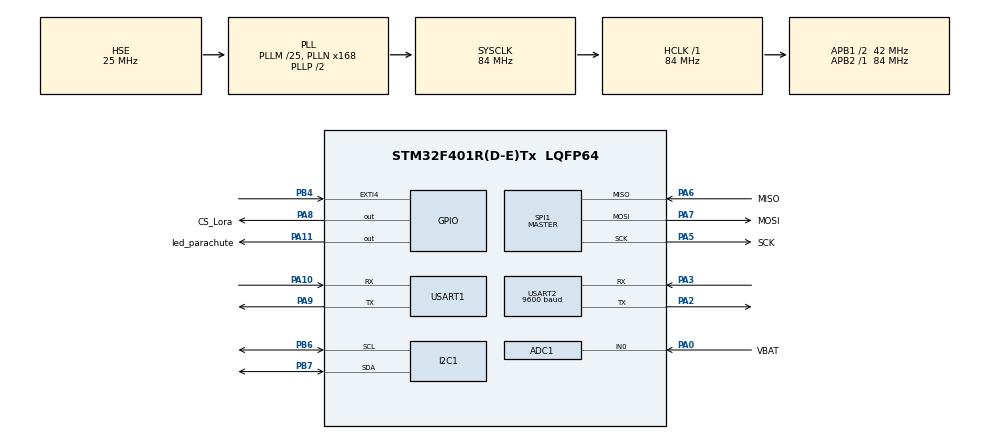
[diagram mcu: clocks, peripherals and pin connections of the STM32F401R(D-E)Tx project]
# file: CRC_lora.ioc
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ADC1.Channel-0\#ChannelRegularConversion=ADC_CHANNEL_0
ADC1.ClockPrescaler=ADC_CLOCK_SYNC_PCLK_DIV8
ADC1.ContinuousConvMode=ENABLE
ADC1.NbrOfConversionFlag=1
ADC1.Rank-0\#ChannelRegularConversion=1
ADC1.SamplingTime-0\#ChannelRegularConversion=ADC_SAMPLETIME_3CYCLES
ADC1.master=1
Dma.I2C1_RX.1.Direction=DMA_PERIPH_TO_MEMORY
Dma.I2C1_RX.1.FIFOMode=DMA_FIFOMODE_DISABLE
Dma.I2C1_RX.1.Instance=DMA1_Stream0
Dma.I2C1_RX.1.MemDataAlignment=DMA_MDATAALIGN_BYTE
Dma.I2C1_RX.1.MemInc=DMA_MINC_ENABLE
Dma.I2C1_RX.1.Mode=DMA_NORMAL
Dma.I2C1_RX.1.PeriphDataAlignment=DMA_PDATAALIGN_BYTE
Dma.I2C1_RX.1.PeriphInc=DMA_PINC_DISABLE
Dma.I2C1_RX.1.Priority=DMA_PRIORITY_LOW
Dma.Request0=USART2_RX
Dma.Request1=I2C1_RX
Dma.USART2_RX.0.Direction=DMA_PERIPH_TO_MEMORY
Dma.USART2_RX.0.FIFOMode=DMA_FIFOMODE_DISABLE
Dma.USART2_RX.0.Instance=DMA1_Stream5
Dma.USART2_RX.0.MemDataAlignment=DMA_MDATAALIGN_BYTE
Dma.USART2_RX.0.MemInc=DMA_MINC_ENABLE
Dma.USART2_RX.0.Mode=DMA_CIRCULAR
Dma.USART2_RX.0.PeriphDataAlignment=DMA_PDATAALIGN_BYTE
Dma.USART2_RX.0.PeriphInc=DMA_PINC_DISABLE
Dma.USART2_RX.0.Priority=DMA_PRIORITY_LOW
Mcu.Family=STM32F4
Mcu.Name=STM32F401R(D-E)Tx
Mcu.Package=LQFP64
NVIC.DMA1_Stream0_IRQn=true\:0\:0\:false\:false\:true\:false\:true\:true
NVIC.DMA1_Stream5_IRQn=true\:0\:0\:false\:false\:true\:false\:true\:true
NVIC.I2C1_EV_IRQn=true\:0\:0\:false\:false\:true\:true\:true\:true
NVIC.PriorityGroup=NVIC_PRIORITYGROUP_4
NVIC.TIM3_IRQn=true\:1\:0\:true\:false\:true\:true\:true\:true
NVIC.USART1_IRQn=true\:0\:0\:false\:false\:true\:true\:true\:true
NVIC.USART2_IRQn=true\:0\:0\:false\:false\:true\:true\:true\:true
PA0-WKUP.GPIO_Label=VBAT
PA0-WKUP.Signal=ADCx_IN0
PA10.Mode=Asynchronous
PA10.Signal=USART1_RX
PA11.GPIO_Label=led_parachute
PA11.Signal=GPIO_Output
PA13.Mode=Serial_Wire
PA13.Signal=SYS_JTMS-SWDIO
PA14.Mode=Serial_Wire
PA14.Signal=SYS_JTCK-SWCLK
PA2.Mode=Asynchronous
PA2.Signal=USART2_TX
PA3.Mode=Asynchronous
PA3.Signal=USART2_RX
PA5.GPIO_Label=SCK
PA5.Mode=Full_Duplex_Master
PA5.Signal=SPI1_SCK
PA6.GPIO_Label=MISO
PA6.Mode=Full_Duplex_Master
PA6.Signal=SPI1_MISO
PA7.GPIO_Label=MOSI
PA7.Mode=Full_Duplex_Master
PA7.Signal=SPI1_MOSI
PA8.GPIO_Label=CS_Lora
PA8.PinState=GPIO_PIN_SET
PA8.Signal=GPIO_Output
PA9.Mode=Asynchronous
PA9.Signal=USART1_TX
PB4.Signal=GPXTI4
PB6.GPIO_Pu=GPIO_PULLUP
PB6.Mode=I2C
PB6.Signal=I2C1_SCL
PB7.GPIO_Pu=GPIO_PULLUP
PB7.Mode=I2C
PB7.Signal=I2C1_SDA
PH0\ -\ OSC_IN.Mode=HSE-External-Oscillator
PH0\ -\ OSC_IN.Signal=RCC_OSC_IN
PH1\ -\ OSC_OUT.Mode=HSE-External-Oscillator
PH1\ -\ OSC_OUT.Signal=RCC_OSC_OUT
ProjectManager.HeapSize=0x200
ProjectManager.StackSize=0x400
ProjectManager.TargetToolchain=STM32CubeIDE
RCC.48MHZClocksFreq_Value=42000000
RCC.AHBFreq_Value=84000000
RCC.APB1CLKDivider=RCC_HCLK_DIV2
RCC.APB1Freq_Value=42000000
RCC.APB1TimFreq_Value=84000000
RCC.APB2Freq_Value=84000000
RCC.APB2TimFreq_Value=84000000
RCC.CortexFreq_Value=84000000
RCC.HCLKFreq_Value=84000000
RCC.HSE_VALUE=25000000
RCC.HSI_VALUE=16000000
RCC.LSE_VALUE=32768
RCC.PLLM=25
RCC.PLLN=168
RCC.PLLSourceVirtual=RCC_PLLSOURCE_HSE
RCC.SYSCLKFreq_VALUE=84000000
RCC.SYSCLKSource=RCC_SYSCLKSOURCE_PLLCLK
RCC.VCOOutputFreq_Value=168000000
SH.ADCx_IN0.0=ADC1_IN0,IN0
SPI1.BaudRatePrescaler=SPI_BAUDRATEPRESCALER_8
SPI1.Direction=SPI_DIRECTION_2LINES
SPI1.Mode=SPI_MODE_MASTER
SPI1.VirtualType=VM_MASTER
TIM3.Channel-PWM\ Generation3\ CH3=TIM_CHANNEL_3
TIM3.Period=19999
TIM3.Prescaler=83
USART1.VirtualMode=VM_ASYNC
USART2.BaudRate=9600
USART2.VirtualMode=VM_ASYNC
VP_TIM3_VS_ClockSourceINT.Mode=Internal
board=custom

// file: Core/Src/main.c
/* USER CODE BEGIN Header */
/**
  ******************************************************************************
  * @file           : main.c
  * @brief          : Main program body
  ******************************************************************************
  * @attention
  *
  * Copyright (c) 2026 STMicroelectronics.
  * All rights reserved.
  *
  * This software is licensed under terms that can be found in the LICENSE file
  * in the root directory of this software component.
  * If no LICENSE file comes with this software, it is provided AS-IS.
  *
  ******************************************************************************
  */
/* USER CODE END Header */
#include "main.h"

/* USER CODE BEGIN Includes */
#include "FlightComputer.h"
#include <string.h>
#include <stdio.h>

#include "minmea.h"
#include "gps.h"
/* USER CODE END Includes */

ADC_HandleTypeDef hadc1;

I2C_HandleTypeDef hi2c1;
DMA_HandleTypeDef hdma_i2c1_rx;

SPI_HandleTypeDef hspi1;

TIM_HandleTypeDef htim3;

UART_HandleTypeDef huart1;
UART_HandleTypeDef huart2;
DMA_HandleTypeDef hdma_usart2_rx;

/* USER CODE BEGIN PV */
char gps_line[MINMEA_MAX_SENTENCE_LENGTH];
uint8_t gps_char;
uint8_t gps_idx = 0;

uint32_t time_buff;
uint32_t time_diff;

uint8_t read_data[128];
uint8_t received_data[128];
uint8_t bytesRecv = 0;
uint8_t parachuteCnt = 0;

#define GPS_BUF_SIZE 128
uint8_t gps_raw_data[GPS_BUF_SIZE];

FlightComputer flight_computer;

extern uint8_t uart_rx_buffer[36];
extern volatile uint8_t new_data_flag;
/* USER CODE END PV */

void SystemClock_Config(void);
static void MX_GPIO_Init(void);
static void MX_DMA_Init(void);
static void MX_SPI1_Init(void);
static void MX_USART1_UART_Init(void);
static void MX_I2C1_Init(void);
static void MX_USART2_UART_Init(void);
static void MX_TIM3_Init(void);
static void MX_ADC1_Init(void);

int main(void)
{

  /* MCU Configuration--------------------------------------------------------*/

  /* Reset of all peripherals, Initializes the Flash interface and the Systick. */
  HAL_Init();

  /* Configure the system clock */
  SystemClock_Config();

  /* Initialize all configured peripherals */
  MX_GPIO_Init();
  MX_DMA_Init();
  MX_SPI1_Init();
  MX_USART1_UART_Init();
  MX_I2C1_Init();
  MX_USART2_UART_Init();
  MX_TIM3_Init();
  MX_ADC1_Init();
  /* USER CODE BEGIN 2 */

  HAL_TIM_PWM_Start(&htim3, TIM_CHANNEL_3);
  uint8_t isSend = 65;
  //HAL_GPIO_WritePin(BUZZ_GPIO_Port, BUZZ_Pin, GPIO_PIN_SET);
  HAL_GPIO_WritePin(LED_R_GPIO_Port, LED_R_Pin, GPIO_PIN_SET);
  HAL_GPIO_WritePin(LED_G_GPIO_Port, LED_G_Pin, GPIO_PIN_SET);
  HAL_Delay(2000);
  HAL_GPIO_WritePin(BUZZ_GPIO_Port, BUZZ_Pin, GPIO_PIN_RESET);
  HAL_GPIO_WritePin(LED_R_GPIO_Port, LED_R_Pin, GPIO_PIN_RESET);
  HAL_GPIO_WritePin(LED_G_GPIO_Port, LED_G_Pin, GPIO_PIN_RESET);
  HAL_UART_Transmit(&huart1, &isSend, 1, 100);
  HAL_Delay(1000);
  FlightComputer_init(&flight_computer, &hspi1, CS_Lora_GPIO_Port, CS_Lora_Pin, &hi2c1, &hadc1, &huart1);
  HAL_UART_Transmit(&huart1,&bytesRecv, 1, 100);
  HAL_UART_Receive_IT(&huart1, uart_rx_buffer, 36);

//  GPS_Init(&huart2, &huart1);

  /* USER CODE END 2 */

  /* Infinite loop */
  /* USER CODE BEGIN WHILE */
  uint8_t isOK = 0;
  while (1)
  {

//	  HAL_GPIO_TogglePin(GPIOA, GPIO_PIN_11);
//	  HAL_Delay(1000);
//	  __HAL_TIM_SET_COMPARE(&htim3, TIM_CHANNEL_3, 500);
//	  HAL_Delay(1000);
//
//	  __HAL_TIM_SET_COMPARE(&htim3, TIM_CHANNEL_3, 1500);
//	  HAL_Delay(1000);
//
//	  __HAL_TIM_SET_COMPARE(&htim3, TIM_CHANNEL_3, 2500);
//	  HAL_Delay(1000);

    FlightComputer_loop(&flight_computer);

//	  GPS_Task();

    /* USER CODE END WHILE */

  }
}

void SystemClock_Config(void)
{
  RCC_OscInitTypeDef RCC_OscInitStruct = {0};
  RCC_ClkInitTypeDef RCC_ClkInitStruct = {0};

  /** Configure the main internal regulator output voltage
  */
  __HAL_RCC_PWR_CLK_ENABLE();
  __HAL_PWR_VOLTAGESCALING_CONFIG(PWR_REGULATOR_VOLTAGE_SCALE2);

  /** Initializes the RCC Oscillators according to the specified parameters
  * in the RCC_OscInitTypeDef structure.
  */
  RCC_OscInitStruct.OscillatorType = RCC_OSCILLATORTYPE_HSE;
  RCC_OscInitStruct.HSEState = RCC_HSE_ON;
  RCC_OscInitStruct.PLL.PLLState = RCC_PLL_ON;
  RCC_OscInitStruct.PLL.PLLSource = RCC_PLLSOURCE_HSE;
  RCC_OscInitStruct.PLL.PLLM = 25;
  RCC_OscInitStruct.PLL.PLLN = 168;
  RCC_OscInitStruct.PLL.PLLP = RCC_PLLP_DIV2;
  RCC_OscInitStruct.PLL.PLLQ = 4;
  if (HAL_RCC_OscConfig(&RCC_OscInitStruct) != HAL_OK)
  {
    Error_Handler();
  }

  /** Initializes the CPU, AHB and APB buses clocks
  */
  RCC_ClkInitStruct.ClockType = RCC_CLOCKTYPE_HCLK|RCC_CLOCKTYPE_SYSCLK
                              |RCC_CLOCKTYPE_PCLK1|RCC_CLOCKTYPE_PCLK2;
  RCC_ClkInitStruct.SYSCLKSource = RCC_SYSCLKSOURCE_PLLCLK;
  RCC_ClkInitStruct.AHBCLKDivider = RCC_SYSCLK_DIV1;
  RCC_ClkInitStruct.APB1CLKDivider = RCC_HCLK_DIV2;
  RCC_ClkInitStruct.APB2CLKDivider = RCC_HCLK_DIV1;

  if (HAL_RCC_ClockConfig(&RCC_ClkInitStruct, FLASH_LATENCY_2) != HAL_OK)
  {
    Error_Handler();
  }
}

static void MX_ADC1_Init(void)
{

  ADC_ChannelConfTypeDef sConfig = {0};

  /** Configure the global features of the ADC (Clock, Resolution, Data Alignment and number of conversion)
  */
  hadc1.Instance = ADC1;
  hadc1.Init.ClockPrescaler = ADC_CLOCK_SYNC_PCLK_DIV8;
  hadc1.Init.Resolution = ADC_RESOLUTION_12B;
  hadc1.Init.ScanConvMode = DISABLE;
  hadc1.Init.ContinuousConvMode = ENABLE;
  hadc1.Init.DiscontinuousConvMode = DISABLE;
  hadc1.Init.ExternalTrigConvEdge = ADC_EXTERNALTRIGCONVEDGE_NONE;
  hadc1.Init.ExternalTrigConv = ADC_SOFTWARE_START;
  hadc1.Init.DataAlign = ADC_DATAALIGN_RIGHT;
  hadc1.Init.NbrOfConversion = 1;
  hadc1.Init.DMAContinuousRequests = DISABLE;
  hadc1.Init.EOCSelection = ADC_EOC_SINGLE_CONV;
  if (HAL_ADC_Init(&hadc1) != HAL_OK)
  {
    Error_Handler();
  }

  /** Configure for the selected ADC regular channel its corresponding rank in the sequencer and its sample time.
  */
  sConfig.Channel = ADC_CHANNEL_0;
  sConfig.Rank = 1;
  sConfig.SamplingTime = ADC_SAMPLETIME_3CYCLES;
  if (HAL_ADC_ConfigChannel(&hadc1, &sConfig) != HAL_OK)
  {
    Error_Handler();
  }

}

static void MX_I2C1_Init(void)
{

  hi2c1.Instance = I2C1;
  hi2c1.Init.ClockSpeed = 100000;
  hi2c1.Init.DutyCycle = I2C_DUTYCYCLE_2;
  hi2c1.Init.OwnAddress1 = 0;
  hi2c1.Init.AddressingMode = I2C_ADDRESSINGMODE_7BIT;
  hi2c1.Init.DualAddressMode = I2C_DUALADDRESS_DISABLE;
  hi2c1.Init.OwnAddress2 = 0;
  hi2c1.Init.GeneralCallMode = I2C_GENERALCALL_DISABLE;
  hi2c1.Init.NoStretchMode = I2C_NOSTRETCH_DISABLE;
  if (HAL_I2C_Init(&hi2c1) != HAL_OK)
  {
    Error_Handler();
  }

}

static void MX_SPI1_Init(void)
{

  /* SPI1 parameter configuration*/
  hspi1.Instance = SPI1;
  hspi1.Init.Mode = SPI_MODE_MASTER;
  hspi1.Init.Direction = SPI_DIRECTION_2LINES;
  hspi1.Init.DataSize = SPI_DATASIZE_8BIT;
  hspi1.Init.CLKPolarity = SPI_POLARITY_LOW;
  hspi1.Init.CLKPhase = SPI_PHASE_1EDGE;
  hspi1.Init.NSS = SPI_NSS_SOFT;
  hspi1.Init.BaudRatePrescaler = SPI_BAUDRATEPRESCALER_8;
  hspi1.Init.FirstBit = SPI_FIRSTBIT_MSB;
  hspi1.Init.TIMode = SPI_TIMODE_DISABLE;
  hspi1.Init.CRCCalculation = SPI_CRCCALCULATION_DISABLE;
  hspi1.Init.CRCPolynomial = 10;
  if (HAL_SPI_Init(&hspi1) != HAL_OK)
  {
    Error_Handler();
  }

}

static void MX_TIM3_Init(void)
{

  TIM_ClockConfigTypeDef sClockSourceConfig = {0};
  TIM_MasterConfigTypeDef sMasterConfig = {0};

  htim3.Instance = TIM3;
  htim3.Init.Prescaler = 83;
  htim3.Init.CounterMode = TIM_COUNTERMODE_UP;
  htim3.Init.Period = 19999;
  htim3.Init.ClockDivision = TIM_CLOCKDIVISION_DIV1;
  htim3.Init.AutoReloadPreload = TIM_AUTORELOAD_PRELOAD_DISABLE;
  if (HAL_TIM_Base_Init(&htim3) != HAL_OK)
  {
    Error_Handler();
  }
  sClockSourceConfig.ClockSource = TIM_CLOCKSOURCE_INTERNAL;
  if (HAL_TIM_ConfigClockSource(&htim3, &sClockSourceConfig) != HAL_OK)
  {
    Error_Handler();
  }
  sMasterConfig.MasterOutputTrigger = TIM_TRGO_RESET;
  sMasterConfig.MasterSlaveMode = TIM_MASTERSLAVEMODE_DISABLE;
  if (HAL_TIMEx_MasterConfigSynchronization(&htim3, &sMasterConfig) != HAL_OK)
  {
    Error_Handler();
  }

}

static void MX_USART1_UART_Init(void)
{

  huart1.Instance = USART1;
  huart1.Init.BaudRate = 115200;
  huart1.Init.WordLength = UART_WORDLENGTH_8B;
  huart1.Init.StopBits = UART_STOPBITS_1;
  huart1.Init.Parity = UART_PARITY_NONE;
  huart1.Init.Mode = UART_MODE_TX_RX;
  huart1.Init.HwFlowCtl = UART_HWCONTROL_NONE;
  huart1.Init.OverSampling = UART_OVERSAMPLING_16;
  if (HAL_UART_Init(&huart1) != HAL_OK)
  {
    Error_Handler();
  }

}

static void MX_USART2_UART_Init(void)
{

  huart2.Instance = USART2;
  huart2.Init.BaudRate = 9600;
  huart2.Init.WordLength = UART_WORDLENGTH_8B;
  huart2.Init.StopBits = UART_STOPBITS_1;
  huart2.Init.Parity = UART_PARITY_NONE;
  huart2.Init.Mode = UART_MODE_TX_RX;
  huart2.Init.HwFlowCtl = UART_HWCONTROL_NONE;
  huart2.Init.OverSampling = UART_OVERSAMPLING_16;
  if (HAL_UART_Init(&huart2) != HAL_OK)
  {
    Error_Handler();
  }

}

static void MX_DMA_Init(void)
{

  /* DMA controller clock enable */
  __HAL_RCC_DMA1_CLK_ENABLE();

  /* DMA interrupt init */
  /* DMA1_Stream0_IRQn interrupt configuration */
  HAL_NVIC_SetPriority(DMA1_Stream0_IRQn, 0, 0);
  HAL_NVIC_EnableIRQ(DMA1_Stream0_IRQn);
  /* DMA1_Stream5_IRQn interrupt configuration */
  HAL_NVIC_SetPriority(DMA1_Stream5_IRQn, 0, 0);
  HAL_NVIC_EnableIRQ(DMA1_Stream5_IRQn);

}

static void MX_GPIO_Init(void)
{
  GPIO_InitTypeDef GPIO_InitStruct = {0};

  /* GPIO Ports Clock Enable */
  __HAL_RCC_GPIOH_CLK_ENABLE();
  __HAL_RCC_GPIOA_CLK_ENABLE();
  __HAL_RCC_GPIOB_CLK_ENABLE();

  /*Configure GPIO pin Output Level */
  HAL_GPIO_WritePin(GPIOA, BUZZ_Pin|led_parachute_Pin, GPIO_PIN_RESET);

  /*Configure GPIO pin Output Level */
  HAL_GPIO_WritePin(GPIOB, LED_R_Pin|LED_G_Pin|LED_B_Pin|LED_Y_Pin, GPIO_PIN_RESET);

  /*Configure GPIO pin Output Level */
  HAL_GPIO_WritePin(CS_Lora_GPIO_Port, CS_Lora_Pin, GPIO_PIN_SET);

  /*Configure GPIO pins : BUZZ_Pin CS_Lora_Pin led_parachute_Pin */
  GPIO_InitStruct.Pin = BUZZ_Pin|CS_Lora_Pin|led_parachute_Pin;
  GPIO_InitStruct.Mode = GPIO_MODE_OUTPUT_PP;
  GPIO_InitStruct.Pull = GPIO_NOPULL;
  GPIO_InitStruct.Speed = GPIO_SPEED_FREQ_LOW;
  HAL_GPIO_Init(GPIOA, &GPIO_InitStruct);

  /*Configure GPIO pins : LED_R_Pin LED_G_Pin LED_B_Pin LED_Y_Pin */
  GPIO_InitStruct.Pin = LED_R_Pin|LED_G_Pin|LED_B_Pin|LED_Y_Pin;
  GPIO_InitStruct.Mode = GPIO_MODE_OUTPUT_PP;
  GPIO_InitStruct.Pull = GPIO_NOPULL;
  GPIO_InitStruct.Speed = GPIO_SPEED_FREQ_LOW;
  HAL_GPIO_Init(GPIOB, &GPIO_InitStruct);

  /*Configure GPIO pin : PB4 */
  GPIO_InitStruct.Pin = GPIO_PIN_4;
  GPIO_InitStruct.Mode = GPIO_MODE_IT_RISING;
  GPIO_InitStruct.Pull = GPIO_NOPULL;
  HAL_GPIO_Init(GPIOB, &GPIO_InitStruct);

}

/* USER CODE BEGIN 4 */
void HAL_UART_RxCpltCallback(UART_HandleTypeDef *huart) {
    if (huart->Instance == USART1) {
    	new_data_flag = 1;
        HAL_UART_Receive_IT(&huart1, uart_rx_buffer, 36);
    }
}

/* USER CODE END 4 */

void Error_Handler(void)
{
  __disable_irq();
  while (1)
  {
  }
}
